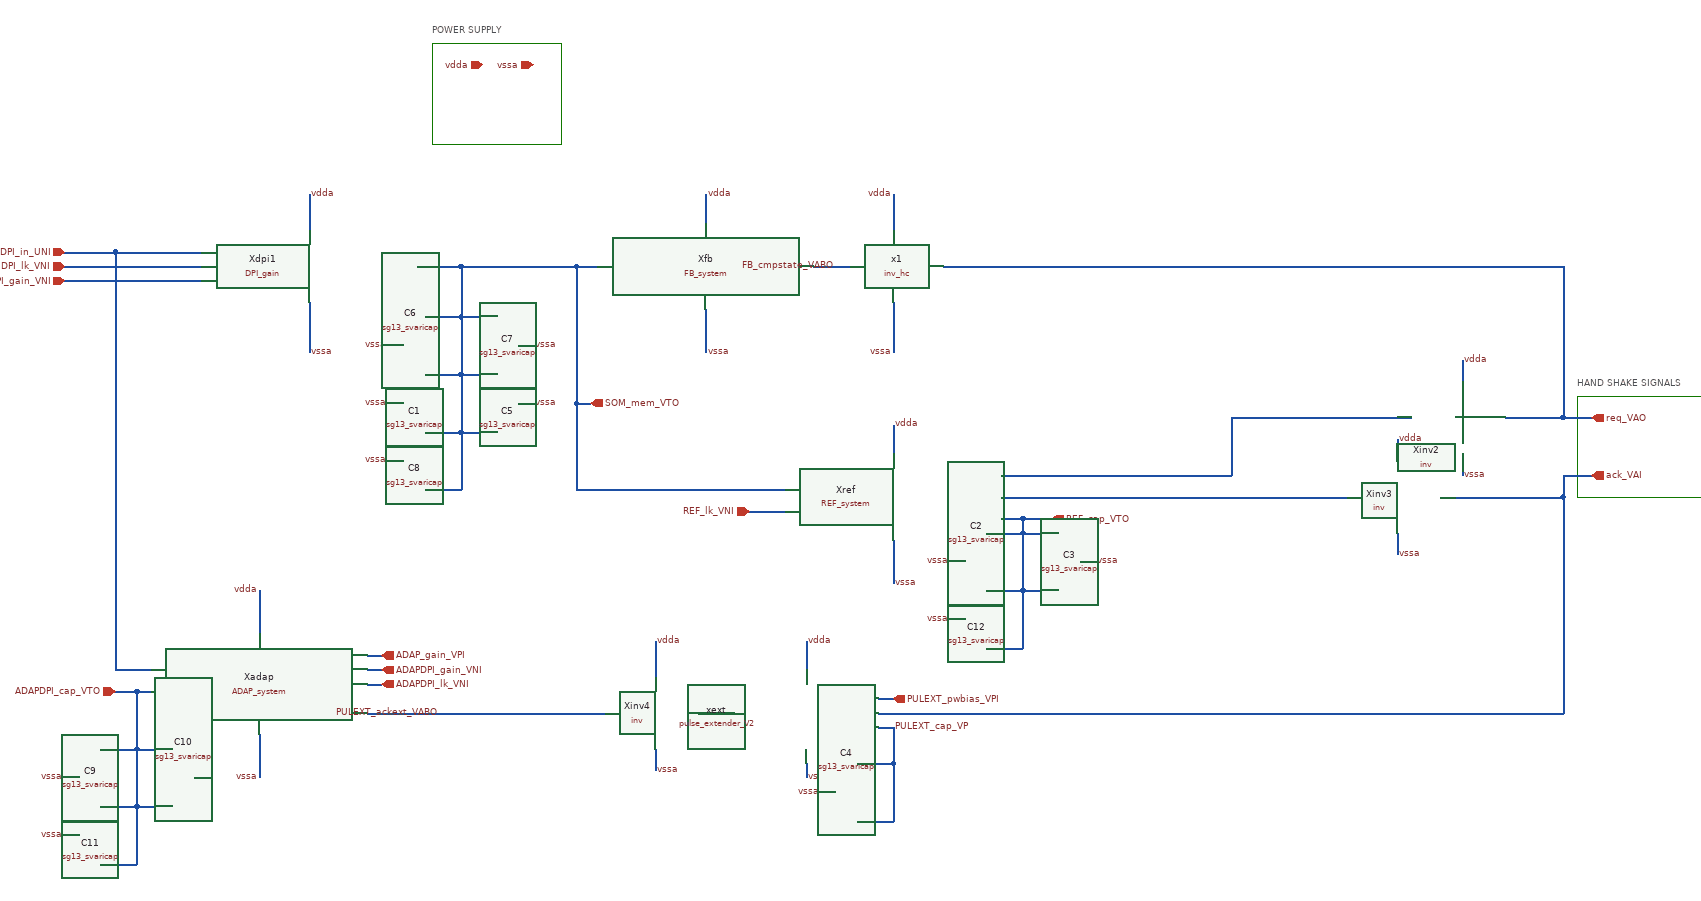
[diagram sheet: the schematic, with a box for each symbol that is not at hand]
v {xschem version=3.4.8RC file_version=1.3}
G {}
K {}
V {}
S {}
F {}
E {}
P 4 5 -190 -440 -10 -440 -10 -300 -190 -300 -190 -440 {}
P 4 5 1400 50 1580 50 1580 190 1400 190 1400 50 {}
T {POWER SUPPLY} -190 -470 0 0 0.4 0.4 {}
T {HAND SHAKE SIGNALS} 1400 20 0 0 0.4 0.4 {}
N 340 -130 390 -130 {lab=FB_cmpstate_VABO}
N 10 -130 40 -130 {lab=SOM_mem_VTO}
N -430 320 -430 380 {lab=vdda}
N 1380 160 1420 160 {lab=ack_VAI}
N 450 -230 450 -180 {lab=vdda}
N 190 -230 190 -190 {lab=vdda}
N 250 210 300 210 {lab=REF_lk_VNI}
N 600 220 630 220 {lab=REF_cap_VTO}
N 630 220 670 220 {lab=REF_cap_VTO}
N -280 450 -260 450 {lab=ADAPDPI_lk_VNI}
N -280 430 -260 430 {lab=ADAPDPI_gain_VNI}
N -280 410 -260 410 {lab=ADAP_gain_VPI}
N -700 -130 -510 -130 {lab=DPI_lk_VNI}
N -630 430 -580 430 {lab=DPI_in_UNI}
N -360 -230 -360 -180 {lab=vdda}
N 10 60 10 180 {lab=SOM_mem_VTO}
N 190 -70 190 -10 {lab=vssa}
N -430 520 -430 580 {lab=vssa}
N 450 -80 450 -10 {lab=vssa}
N -360 -80 -360 -10 {lab=vssa}
N 630 220 630 240 {lab=REF_cap_VTO}
N 330 560 330 580 {lab=vssa}
N 10 60 30 60 {lab=SOM_mem_VTO}
N 10 -130 10 60 {lab=SOM_mem_VTO}
N 430 470 450 470 {lab=PULEXT_pwbias_VPI}
N 10 180 300 180 {lab=SOM_mem_VTO}
N 330 390 330 430 {lab=vdda}
N 1380 190 1380 490 {lab=ack_VAI}
N -700 -110 -510 -110 {lab=DPI_gain_VNI}
N -600 460 -580 460 {lab=ADAPDPI_cap_VTO}
N -630 460 -600 460 {lab=ADAPDPI_cap_VTO}
N 1240 130 1240 160 {lab=vssa}
N 1240 0 1240 30 {lab=vdda}
N 1380 80 1420 80 {lab=req_VAO}
N 1380 -130 1380 80 {lab=req_VAO}
N 520 -130 1380 -130 {lab=req_VAO}
N 1150 240 1150 270 {lab=vssa}
N 1150 110 1150 140 {lab=vdda}
N 1300 80 1380 80 {lab=req_VAO}
N 920 80 1170 80 {lab=#net1}
N 920 80 920 160 {lab=#net1}
N 600 160 920 160 {lab=#net1}
N 600 190 1080 190 {lab=#net2}
N 1210 190 1380 190 {lab=ack_VAI}
N 1380 160 1380 190 {lab=ack_VAI}
N -630 -150 -630 430 {lab=DPI_in_UNI}
N -630 -150 -510 -150 {lab=DPI_in_UNI}
N -700 -150 -630 -150 {lab=DPI_in_UNI}
N 180 490 230 490 {lab=#net3}
N 430 490 1380 490 {lab=ack_VAI}
N 120 540 120 570 {lab=vssa}
N -280 490 50 490 {lab=PULEXT_ackext_VABO}
N 120 390 120 440 {lab=vdda}
N -150 -130 10 -130 {lab=SOM_mem_VTO}
N -150 -60 -150 20 {lab=SOM_mem_VTO}
N -210 -130 -150 -130 {lab=SOM_mem_VTO}
N -600 460 -600 540 {lab=ADAPDPI_cap_VTO}
N -250 -20 -230 -20 {lab=vssa}
N -70 -20 -50 -20 {lab=vssa}
N -150 20 -100 20 {lab=SOM_mem_VTO}
N -150 -60 -100 -60 {lab=SOM_mem_VTO}
N -200 -60 -150 -60 {lab=SOM_mem_VTO}
N -200 20 -150 20 {lab=SOM_mem_VTO}
N 350 600 370 600 {lab=vssa}
N 400 560 450 560 {lab=PULEXT_cap_VP}
N 430 510 450 510 {lab=PULEXT_cap_VP}
N 450 510 450 560 {lab=PULEXT_cap_VP}
N 450 560 450 640 {lab=PULEXT_cap_VP}
N 400 640 450 640 {lab=PULEXT_cap_VP}
N -250 60 -230 60 {lab=vssa}
N -70 60 -50 60 {lab=vssa}
N -150 100 -100 100 {lab=SOM_mem_VTO}
N -150 20 -150 100 {lab=SOM_mem_VTO}
N -200 100 -150 100 {lab=SOM_mem_VTO}
N -150 -130 -150 -60 {lab=SOM_mem_VTO}
N -250 140 -230 140 {lab=vssa}
N -150 100 -150 180 {lab=SOM_mem_VTO}
N -200 180 -150 180 {lab=SOM_mem_VTO}
N -600 540 -550 540 {lab=ADAPDPI_cap_VTO}
N -650 540 -600 540 {lab=ADAPDPI_cap_VTO}
N -700 580 -680 580 {lab=vssa}
N -520 580 -500 580 {lab=vssa}
N -600 620 -550 620 {lab=ADAPDPI_cap_VTO}
N -600 540 -600 620 {lab=ADAPDPI_cap_VTO}
N -650 620 -600 620 {lab=ADAPDPI_cap_VTO}
N -700 660 -680 660 {lab=vssa}
N -600 620 -600 700 {lab=ADAPDPI_cap_VTO}
N -650 700 -600 700 {lab=ADAPDPI_cap_VTO}
N 630 240 680 240 {lab=REF_cap_VTO}
N 580 240 630 240 {lab=REF_cap_VTO}
N 530 280 550 280 {lab=vssa}
N 710 280 730 280 {lab=vssa}
N 630 320 680 320 {lab=REF_cap_VTO}
N 630 240 630 320 {lab=REF_cap_VTO}
N 580 320 630 320 {lab=REF_cap_VTO}
N 530 360 550 360 {lab=vssa}
N 630 320 630 400 {lab=REF_cap_VTO}
N 580 400 630 400 {lab=REF_cap_VTO}
N 450 250 450 310 {lab=vssa}
N 450 90 450 130 {lab=vdda}
C {FB_system.sym} 190 -130 0 0 {name=Xfb}
C {ADAP_system.sym} -430 450 0 1 {name=Xadap}
C {REF_system.sym} 450 190 0 0 {name=Xref}
C {ipin.sym} 250 210 0 0 {name=p1 lab=REF_lk_VNI}
C {iopin.sym} -50 -410 1 0 {name=p2 lab=vssa}
C {iopin.sym} -120 -410 1 0 {name=p3 lab=vdda}
C {opin.sym} 1420 80 0 0 {name=p4 lab=req_VAO
}
C {ipin.sym} 1420 160 0 1 {name=p5 lab=ack_VAI}
C {ipin.sym} -700 -130 0 0 {name=p8 lab=DPI_lk_VNI
}
C {ipin.sym} -260 410 0 1 {name=p9 lab=ADAP_gain_VPI
}
C {ipin.sym} -260 430 0 1 {name=p10 lab=ADAPDPI_gain_VNI
}
C {ipin.sym} -260 450 0 1 {name=p11 lab=ADAPDPI_lk_VNI
}
C {opin.sym} -630 460 0 1 {name=p12 lab=ADAPDPI_cap_VTO}
C {opin.sym} 30 60 0 0 {name=p13 lab=SOM_mem_VTO}
C {lab_wire.sym} 370 -130 3 0 {name=p14 sig_type=std_logic lab=FB_cmpstate_VABO}
C {opin.sym} 670 220 0 0 {name=p15 lab=REF_cap_VTO}
C {pulse_extender_V2.sym} 280 510 0 1 {name=xext}
C {lab_pin.sym} -360 -230 0 1 {name=p16 sig_type=std_logic lab=vdda}
C {lab_pin.sym} 190 -230 0 1 {name=p17 sig_type=std_logic lab=vdda}
C {lab_pin.sym} 450 -230 0 0 {name=p18 sig_type=std_logic lab=vdda}
C {lab_pin.sym} 450 90 0 1 {name=p20 sig_type=std_logic lab=vdda}
C {lab_pin.sym} -430 320 0 0 {name=p21 sig_type=std_logic lab=vdda}
C {lab_pin.sym} -360 -10 0 1 {name=p22 sig_type=std_logic lab=vssa}
C {lab_pin.sym} 190 -10 0 1 {name=p23 sig_type=std_logic lab=vssa}
C {lab_pin.sym} 450 -10 0 0 {name=p25 sig_type=std_logic lab=vssa}
C {lab_pin.sym} 450 310 0 1 {name=p27 sig_type=std_logic lab=vssa}
C {lab_pin.sym} -430 580 0 0 {name=p28 sig_type=std_logic lab=vssa}
C {lab_pin.sym} 330 390 0 1 {name=p31 sig_type=std_logic lab=vdda}
C {lab_pin.sym} 330 580 0 1 {name=p32 sig_type=std_logic lab=vssa}
C {ipin.sym} 450 470 0 1 {name=p34 lab=PULEXT_pwbias_VPI}
C {lab_pin.sym} -180 490 3 0 {name=p37 sig_type=std_logic lab=PULEXT_ackext_VABO}
C {ipin.sym} -700 -110 0 0 {name=p7 lab=DPI_gain_VNI
}
C {iopin.sym} -700 -150 2 0 {name=p36 lab=DPI_in_UNI}
C {inv.sym} 1150 80 0 1 {name=Xinv2}
C {lab_pin.sym} 1240 0 0 1 {name=p6 sig_type=std_logic lab=vdda}
C {lab_pin.sym} 1240 160 0 1 {name=p19 sig_type=std_logic lab=vssa}
C {inv.sym} 1060 190 0 1 {name=Xinv3}
C {lab_pin.sym} 1150 110 0 1 {name=p24 sig_type=std_logic lab=vdda}
C {lab_pin.sym} 1150 270 0 1 {name=p26 sig_type=std_logic lab=vssa}
C {inv.sym} 30 490 0 1 {name=Xinv4}
C {lab_pin.sym} 120 390 0 1 {name=p35 sig_type=std_logic lab=vdda}
C {lab_pin.sym} 120 570 0 1 {name=p38 sig_type=std_logic lab=vssa}
C {lab_pin.sym} -50 -20 0 1 {name=p52 sig_type=std_logic lab=vssa}
C {lab_pin.sym} -250 -20 0 0 {name=p53 sig_type=std_logic lab=vssa}
C {sg13g2_pr/sg13_svaricap.sym} -200 -20 3 1 {name=C6 
model=sg13_hv_svaricap 
w=9.74u 
l=0.8u 
Nx=3
body=vssa
spiceprefix=X
}
C {sg13g2_pr/sg13_svaricap.sym} -100 -20 1 0 {name=C7 
model=sg13_hv_svaricap 
w=9.74u 
l=0.8u 
Nx=3
body=vssa
spiceprefix=X
}
C {lab_pin.sym} 350 600 0 0 {name=p50 sig_type=std_logic lab=vssa}
C {sg13g2_pr/sg13_svaricap.sym} 400 600 3 1 {name=C4 
model=sg13_hv_svaricap 
w=3.74u 
l=0.3u 
Nx=1 
body=vssa
spiceprefix=X
}
C {inv_hc.sym} 540 -130 0 0 {name=x1}
C {DPI_gain.sym} -360 -130 0 0 {name=Xdpi1}
C {lab_pin.sym} -50 60 0 1 {name=p39 sig_type=std_logic lab=vssa}
C {lab_pin.sym} -250 60 0 0 {name=p45 sig_type=std_logic lab=vssa}
C {sg13g2_pr/sg13_svaricap.sym} -200 60 3 1 {name=C1 
model=sg13_hv_svaricap 
w=9.74u 
l=0.8u 
Nx=3 
body=vssa
spiceprefix=X
}
C {sg13g2_pr/sg13_svaricap.sym} -100 60 1 0 {name=C5 
model=sg13_hv_svaricap 
w=9.74u 
l=0.8u 
Nx=3
body=vssa
spiceprefix=X
}
C {lab_pin.sym} -250 140 0 0 {name=p29 sig_type=std_logic lab=vssa}
C {sg13g2_pr/sg13_svaricap.sym} -200 140 3 1 {name=C8 
model=sg13_hv_svaricap 
w=9.74u 
l=0.8u 
Nx=3 
body=vssa
spiceprefix=X
}
C {lab_pin.sym} -500 580 1 1 {name=p40 sig_type=std_logic lab=vssa}
C {lab_pin.sym} -700 580 0 0 {name=p41 sig_type=std_logic lab=vssa}
C {sg13g2_pr/sg13_svaricap.sym} -650 580 3 1 {name=C9 
model=sg13_hv_svaricap 
w=9.74u 
l=0.8u 
Nx=3 
body=vssa
spiceprefix=X
}
C {sg13g2_pr/sg13_svaricap.sym} -550 580 1 0 {name=C10 
model=sg13_hv_svaricap 
w=9.74u 
l=0.8u 
Nx=3
body=vssa
spiceprefix=X
}
C {lab_pin.sym} -700 660 0 0 {name=p44 sig_type=std_logic lab=vssa}
C {sg13g2_pr/sg13_svaricap.sym} -650 660 3 1 {name=C11 
model=sg13_hv_svaricap 
w=9.74u 
l=0.8u 
Nx=3 
body=vssa
spiceprefix=X
}
C {lab_pin.sym} 730 280 0 1 {name=p42 sig_type=std_logic lab=vssa}
C {lab_pin.sym} 530 280 0 0 {name=p46 sig_type=std_logic lab=vssa}
C {sg13g2_pr/sg13_svaricap.sym} 580 280 3 1 {name=C2 
model=sg13_hv_svaricap 
w=9.74u 
l=0.8u 
Nx=3 
body=vssa
spiceprefix=X
}
C {sg13g2_pr/sg13_svaricap.sym} 680 280 1 0 {name=C3 
model=sg13_hv_svaricap 
w=9.74u 
l=0.8u 
Nx=3
body=vssa
spiceprefix=X
}
C {lab_pin.sym} 530 360 0 0 {name=p48 sig_type=std_logic lab=vssa}
C {sg13g2_pr/sg13_svaricap.sym} 580 360 3 1 {name=C12 
model=sg13_hv_svaricap 
w=9.74u 
l=0.8u 
Nx=3 
body=vssa
spiceprefix=X
}
C {lab_pin.sym} 450 510 0 1 {name=p49 sig_type=std_logic lab=PULEXT_cap_VP}
